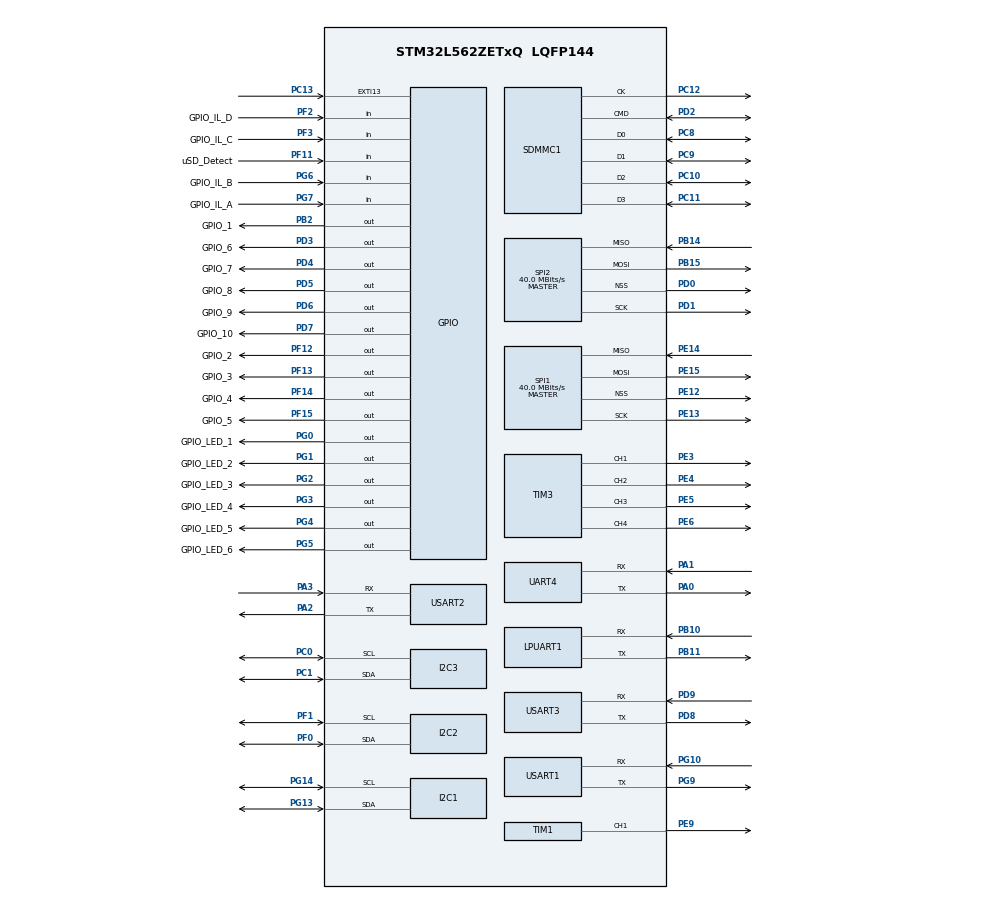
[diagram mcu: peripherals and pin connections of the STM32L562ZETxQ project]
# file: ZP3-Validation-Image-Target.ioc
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Dma.Request0=TIM1_CH1
Dma.TIM1_CH1.0.Channel_PRIV_NPRIV=DMA_CHANNEL_NPRIV_DISABLE
Dma.TIM1_CH1.0.Direction=DMA_MEMORY_TO_PERIPH
Dma.TIM1_CH1.0.EventEnable=DISABLE
Dma.TIM1_CH1.0.Instance=DMA1_Channel1
Dma.TIM1_CH1.0.MemDataAlignment=DMA_MDATAALIGN_HALFWORD
Dma.TIM1_CH1.0.MemInc=DMA_MINC_ENABLE
Dma.TIM1_CH1.0.Mode=DMA_NORMAL
Dma.TIM1_CH1.0.PeriphDataAlignment=DMA_PDATAALIGN_HALFWORD
Dma.TIM1_CH1.0.PeriphInc=DMA_PINC_DISABLE
Dma.TIM1_CH1.0.Polarity=HAL_DMAMUX_REQ_GEN_RISING
Dma.TIM1_CH1.0.Priority=DMA_PRIORITY_LOW
Dma.TIM1_CH1.0.RequestNumber=1
Dma.TIM1_CH1.0.SignalID=NONE
Dma.TIM1_CH1.0.SyncEnable=DISABLE
Dma.TIM1_CH1.0.SyncPolarity=HAL_DMAMUX_SYNC_NO_EVENT
Dma.TIM1_CH1.0.SyncRequestNumber=1
Dma.TIM1_CH1.0.SyncSignalID=NONE
I2C1.Timing=0x10909CEC
I2C2.Timing=0x10909CEC
I2C3.Timing=0x10909CEC
Mcu.Family=STM32L5
Mcu.Name=STM32L562ZETxQ
Mcu.Package=LQFP144
NVIC.DMA1_Channel1_IRQn=true\:0\:0\:false\:false\:true\:false\:true\:true
NVIC.PriorityGroup=NVIC_PRIORITYGROUP_3
NVIC.SDMMC1_IRQn=true\:0\:0\:false\:false\:true\:true\:true\:true
PA0.Mode=Asynchronous
PA0.Signal=UART4_TX
PA1.Mode=Asynchronous
PA1.Signal=UART4_RX
PA11.Signal=USART1_CTS
PA12.Signal=USART1_RTS
PA13\ (JTMS/SWDIO).GPIO_Label=SWDIO
PA13\ (JTMS/SWDIO).Signal=DEBUG_JTMS-SWDIO
PA14\ (JTCK/SWCLK).GPIO_Label=SWCLK
PA14\ (JTCK/SWCLK).Signal=DEBUG_JTCK-SWCLK
PA15\ (JTDI).Signal=UART4_RTS
PA2.Mode=Asynchronous
PA2.Signal=USART2_TX
PA3.Mode=Asynchronous
PA3.Signal=USART2_RX
PA4.GPIO_Label=PWR_SENSE
PA4.Signal=ADCx_IN9
PA6.Signal=ADCx_IN11
PA7.Signal=ADCx_IN12
PB0.Signal=ADCx_IN15
PB1.GPIO_Label=VBAT_A_SENSE
PB1.Signal=ADCx_IN16
PB10.Mode=Asynchronous
PB10.Signal=LPUART1_RX
PB11.Mode=Asynchronous
PB11.Signal=LPUART1_TX
PB14.Mode=Full_Duplex_Master
PB14.Signal=SPI2_MISO
PB15.Mode=Full_Duplex_Master
PB15.Signal=SPI2_MOSI
PB2.GPIO_Label=GPIO_1
PB2.Signal=GPIO_Output
PB3\ (JTDO/TRACESWO).GPIO_Label=SWO
PB3\ (JTDO/TRACESWO).Signal=DEBUG_JTDO-SWO
PB7.Signal=UART4_CTS
PB8.Signal=S_TIM16_CH1
PB9.Signal=S_TIM17_CH1
PC0.Mode=I2C
PC0.Signal=I2C3_SCL
PC1.Mode=I2C
PC1.Signal=I2C3_SDA
PC10.Mode=SD_4_bits_Wide_bus
PC10.Signal=SDMMC1_D2
PC11.Mode=SD_4_bits_Wide_bus
PC11.Signal=SDMMC1_D3
PC12.Mode=SD_4_bits_Wide_bus
PC12.Signal=SDMMC1_CK
PC13.Privilege=EXTI_LINE_PRIV
PC13.Signal=GPXTI13
PC2.GPIO_Label=VBAT_B_SENSE
PC2.Signal=ADCx_IN3
PC8.Mode=SD_4_bits_Wide_bus
PC8.Signal=SDMMC1_D0
PC9.Mode=SD_4_bits_Wide_bus
PC9.Signal=SDMMC1_D1
PD0.Mode=NSS_Signal_Hard_Output
PD0.Signal=SPI2_NSS
PD1.Mode=Full_Duplex_Master
PD1.Signal=SPI2_SCK
PD12.Signal=S_TIM4_CH1
PD13.Signal=S_TIM4_CH2
PD14.Signal=S_TIM4_CH3
PD2.Mode=SD_4_bits_Wide_bus
PD2.Signal=SDMMC1_CMD
PD3.GPIO_Label=GPIO_6
PD3.Signal=GPIO_Output
PD4.GPIO_Label=GPIO_7
PD4.Signal=GPIO_Output
PD5.GPIO_Label=GPIO_8
PD5.Signal=GPIO_Output
PD6.GPIO_Label=GPIO_9
PD6.Signal=GPIO_Output
PD7.GPIO_Label=GPIO_10
PD7.Signal=GPIO_Output
PD8.Mode=Asynchronous
PD8.Signal=USART3_TX
PD9.Mode=Asynchronous
PD9.Signal=USART3_RX
PE11.Signal=S_TIM1_CH2
PE12.Mode=NSS_Signal_Hard_Output
PE12.Signal=SPI1_NSS
PE13.Mode=Full_Duplex_Master
PE13.Signal=SPI1_SCK
PE14.Mode=Full_Duplex_Master
PE14.Signal=SPI1_MISO
PE15.Mode=Full_Duplex_Master
PE15.Signal=SPI1_MOSI
PE3.Signal=S_TIM3_CH1
PE4.Signal=S_TIM3_CH2
PE5.Signal=S_TIM3_CH3
PE6.Signal=S_TIM3_CH4
PE9.Signal=S_TIM1_CH1
PF0.Mode=I2C
PF0.Signal=I2C2_SDA
PF1.Mode=I2C
PF1.Signal=I2C2_SCL
PF11.GPIO_Label=uSD_Detect
PF11.Signal=GPIO_Input
PF12.GPIO_Label=GPIO_2
PF12.Signal=GPIO_Output
PF13.GPIO_Label=GPIO_3
PF13.Signal=GPIO_Output
PF14.GPIO_Label=GPIO_4
PF14.Signal=GPIO_Output
PF15.GPIO_Label=GPIO_5
PF15.Signal=GPIO_Output
PF2.GPIO_Label=GPIO_IL_D
PF2.Signal=GPIO_Input
PF3.GPIO_Label=GPIO_IL_C
PF3.Signal=GPIO_Input
PF6.Signal=S_TIM5_CH1
PF7.Signal=S_TIM5_CH2
PF8.Signal=S_TIM5_CH3
PF9.Signal=S_TIM5_CH4
PG0.GPIO_Label=GPIO_LED_1
PG0.Signal=GPIO_Output
PG1.GPIO_Label=GPIO_LED_2
PG1.Signal=GPIO_Output
PG10.Mode=Asynchronous
PG10.Signal=USART1_RX
PG13.Mode=I2C
PG13.Signal=I2C1_SDA
PG14.Mode=I2C
PG14.Signal=I2C1_SCL
PG2.GPIO_Label=GPIO_LED_3
PG2.Signal=GPIO_Output
PG3.GPIO_Label=GPIO_LED_4
PG3.Signal=GPIO_Output
PG4.GPIO_Label=GPIO_LED_5
PG4.Signal=GPIO_Output
PG5.GPIO_Label=GPIO_LED_6
PG5.Signal=GPIO_Output
PG6.GPIO_Label=GPIO_IL_B
PG6.Signal=GPIO_Input
PG7.GPIO_Label=GPIO_IL_A
PG7.Signal=GPIO_Input
PG9.Mode=Asynchronous
PG9.Signal=USART1_TX
PH0-OSC_IN\ (PH0).Mode=HSE-External-Oscillator
PH0-OSC_IN\ (PH0).Signal=RCC_OSC_IN
PH1-OSC_OUT\ (PH1).Mode=HSE-External-Oscillator
PH1-OSC_OUT\ (PH1).Signal=RCC_OSC_OUT
ProjectManager.HeapSize=0x400
ProjectManager.StackSize=0x800
ProjectManager.TargetToolchain=STM32CubeIDE
RCC.AHBFreq_Value=80000000
RCC.APB1Freq_Value=80000000
RCC.APB1TimFreq_Value=80000000
RCC.APB2Freq_Value=80000000
RCC.APB2TimFreq_Value=80000000
RCC.CortexFreq_Value=80000000
RCC.HCLKFreq_Value=80000000
RCC.HSE_VALUE=16000000
RCC.HSI48_VALUE=48000000
RCC.HSI_VALUE=16000000
RCC.LSE_VALUE=32768
RCC.MSI_VALUE=4000000
RCC.PLLN=40
RCC.SYSCLKFreq_VALUE=80000000
RCC.SYSCLKSource=RCC_SYSCLKSOURCE_PLLCLK
RCC.VCOOutputFreq_Value=160000000
SH.ADCx_IN11.0=ADC1_IN11
SH.ADCx_IN12.0=ADC1_IN12
SH.ADCx_IN15.0=ADC1_IN15
SH.ADCx_IN16.0=ADC2_IN16
SH.ADCx_IN3.0=ADC2_IN3
SH.ADCx_IN9.0=ADC2_IN9
SH.S_TIM16_CH1.0=TIM16_CH1
SH.S_TIM17_CH1.0=TIM17_CH1
SH.S_TIM1_CH1.0=TIM1_CH1,PWM Generation1 CH1
SH.S_TIM1_CH2.0=TIM1_CH2
SH.S_TIM3_CH1.0=TIM3_CH1,PWM Generation1 CH1
SH.S_TIM3_CH2.0=TIM3_CH2,PWM Generation2 CH2
SH.S_TIM3_CH3.0=TIM3_CH3,PWM Generation3 CH3
SH.S_TIM3_CH4.0=TIM3_CH4,PWM Generation4 CH4
SH.S_TIM4_CH1.0=TIM4_CH1
SH.S_TIM4_CH2.0=TIM4_CH2
SH.S_TIM4_CH3.0=TIM4_CH3
SH.S_TIM5_CH1.0=TIM5_CH1
SH.S_TIM5_CH2.0=TIM5_CH2
SH.S_TIM5_CH3.0=TIM5_CH3
SH.S_TIM5_CH4.0=TIM5_CH4
SPI1.BaudRatePrescaler=SPI_BAUDRATEPRESCALER_2
SPI1.CalculateBaudRate=40.0 MBits/s
SPI1.Direction=SPI_DIRECTION_2LINES
SPI1.Mode=SPI_MODE_MASTER
SPI1.VirtualNSS=VM_NSSHARD
SPI1.VirtualType=VM_MASTER
SPI2.BaudRatePrescaler=SPI_BAUDRATEPRESCALER_2
SPI2.CalculateBaudRate=40.0 MBits/s
SPI2.Direction=SPI_DIRECTION_2LINES
SPI2.Mode=SPI_MODE_MASTER
SPI2.VirtualNSS=VM_NSSHARD
SPI2.VirtualType=VM_MASTER
TIM1.Channel-PWM\ Generation1\ CH1=TIM_CHANNEL_1
TIM1.Period=100-1
TIM3.AutoReloadPreload=TIM_AUTORELOAD_PRELOAD_ENABLE
TIM3.Channel-PWM\ Generation1\ CH1=TIM_CHANNEL_1
TIM3.Channel-PWM\ Generation2\ CH2=TIM_CHANNEL_2
TIM3.Channel-PWM\ Generation3\ CH3=TIM_CHANNEL_3
TIM3.Channel-PWM\ Generation4\ CH4=TIM_CHANNEL_4
USART1.VirtualMode-Asynchronous=VM_ASYNC
USART2.VirtualMode-Asynchronous=VM_ASYNC
USART3.VirtualMode-Asynchronous=VM_ASYNC
VP_FATFS_VS_SDIO.Mode=SDIO
VP_PWR_VS_DBSignals.Mode=DisableDeadBatterySignals
VP_PWR_VS_SECSignals.Mode=Security/Privilege
VP_TIM3_VS_ClockSourceINT.Mode=Internal
board=custom

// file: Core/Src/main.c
/* USER CODE BEGIN Header */

/**

  ******************************************************************************

  * @file           : main.c

  * @brief          : Main program body

  ******************************************************************************

  * @attention

  *

  * Copyright (c) 2024 STMicroelectronics.

  * All rights reserved.

  *

  * This software is licensed under terms that can be found in the LICENSE file

  * in the root directory of this software component.

  * If no LICENSE file comes with this software, it is provided AS-IS.

  *

  ******************************************************************************

  */

/* USER CODE END Header */

#include "main.h"

#include "dma.h"

#include "app_fatfs.h"

#include "i2c.h"

#include "usart.h"

#include "sdmmc.h"

#include "spi.h"

#include "tim.h"

#include "gpio.h"

/* USER CODE BEGIN Includes */

#include "string.h"

#include "stdio.h"

/* USER CODE END Includes */

/* USER CODE BEGIN PD */

#define LOW GPIO_PIN_RESET

#define HIGH GPIO_PIN_SET

/* USER CODE END PD */

/* USER CODE BEGIN PV */
TIM_HandleTypeDef htim3;
uint16_t pwmData[24];

int datasentflag = 0;

/* USER CODE END PV */

/* USER CODE BEGIN PFP */

void LED_Test(void);

void GPIO_Test(void);

void UART_Test(void);

void I2C_Test(void);

void SPI_Test(void);
void SPI_Test_2(void);

void PWM_Gen(void);

void PWM_DMA_Gen(TIM_HandleTypeDef *);

void Transmit_Sequence(TIM_HandleTypeDef *, uint32_t);

void ADC_Test(void);

void MicroSD_Test(void);

void Interlock_Check(void);

void SystemClock_Config(void);
void Error_Handler(void);
void MX_GPIO_Init(void);
void MX_TIM3_Init(void);
void Start_PWM(void);

/* USER CODE END PFP */

int main(void){

  /* MCU Configuration--------------------------------------------------------*/

  /* Reset of all peripherals, Initializes the Flash interface and the Systick. */

  HAL_Init();

  /* Configure the system clock */

  SystemClock_Config();

  /* Initialize all configured peripherals */

  MX_GPIO_Init();

  MX_DMA_Init();

  MX_USART2_UART_Init();

  MX_USART3_UART_Init();

  MX_SDMMC1_SD_Init();

  if (MX_FATFS_Init() != APP_OK) {

    Error_Handler();

  }

  MX_I2C1_Init();

  MX_I2C2_Init();

  MX_I2C3_Init();

  MX_SPI1_Init();

  MX_SPI2_Init();

  MX_TIM1_Init();

  MX_TIM3_Init();

  MX_USART1_UART_Init();

  MX_LPUART1_UART_Init();

  MX_UART4_Init();

  HAL_TIM_PWM_Start(&htim3, TIM_CHANNEL_1);

  HAL_TIM_PWM_Start(&htim3, TIM_CHANNEL_2);

  HAL_TIM_PWM_Start(&htim3, TIM_CHANNEL_3);

  HAL_TIM_PWM_Start(&htim3, TIM_CHANNEL_4);

  /* Infinite loop */

  while (1)
  {

  }

}

void SystemClock_Config(void)
{
  RCC_OscInitTypeDef RCC_OscInitStruct = {0};
  RCC_ClkInitTypeDef RCC_ClkInitStruct = {0};

  // Configure the main internal regulator output voltage
  if (HAL_PWREx_ControlVoltageScaling(PWR_REGULATOR_VOLTAGE_SCALE1) != HAL_OK)
  {
    Error_Handler();
  }

  // Initializes the RCC Oscillators according to the specified parameters
  RCC_OscInitStruct.OscillatorType = RCC_OSCILLATORTYPE_HSE;
  RCC_OscInitStruct.HSEState = RCC_HSE_ON;
  RCC_OscInitStruct.PLL.PLLState = RCC_PLL_ON;
  RCC_OscInitStruct.PLL.PLLSource = RCC_PLLSOURCE_HSE;
  RCC_OscInitStruct.PLL.PLLM = 1; // Division factor for PLL input clock (HSE / PLLM)
  RCC_OscInitStruct.PLL.PLLN = 72; // Multiplication factor for PLL VCO (VCO = HSE * PLLN)
  RCC_OscInitStruct.PLL.PLLP = RCC_PLLP_DIV2; // Division factor for main system clock (VCO / PLLP)
  RCC_OscInitStruct.PLL.PLLQ = RCC_PLLQ_DIV2; // Division factor for USB clock (48 MHz)
  RCC_OscInitStruct.PLL.PLLR = RCC_PLLR_DIV2; // Division factor for other clock sources

  if (HAL_RCC_OscConfig(&RCC_OscInitStruct) != HAL_OK)
  {
    Error_Handler();
  }

  // Initializes the CPU, AHB and APB buses clocks
  RCC_ClkInitStruct.ClockType = RCC_CLOCKTYPE_HCLK | RCC_CLOCKTYPE_SYSCLK |
                                RCC_CLOCKTYPE_PCLK1 | RCC_CLOCKTYPE_PCLK2;
  RCC_ClkInitStruct.SYSCLKSource = RCC_SYSCLKSOURCE_PLLCLK;
  RCC_ClkInitStruct.AHBCLKDivider = RCC_SYSCLK_DIV1;
  RCC_ClkInitStruct.APB1CLKDivider = RCC_HCLK_DIV2;
  RCC_ClkInitStruct.APB2CLKDivider = RCC_HCLK_DIV1;

  if (HAL_RCC_ClockConfig(&RCC_ClkInitStruct, FLASH_LATENCY_2) != HAL_OK)
  {
    Error_Handler();
  }

  // Configure the Systick interrupt time
  HAL_SYSTICK_Config(HAL_RCC_GetHCLKFreq()/1000);

  // Configure the Systick
  HAL_SYSTICK_CLKSourceConfig(SYSTICK_CLKSOURCE_HCLK);

  // SysTick_IRQn interrupt configuration
  HAL_NVIC_SetPriority(SysTick_IRQn, 0, 0);

  /** Enable MSI Auto calibration

  */

  HAL_RCCEx_EnableMSIPLLMode();

}

void MX_TIM3_Init(void)
{
  TIM_OC_InitTypeDef sConfigOC = {0};

  // Enable timer clock
  __HAL_RCC_TIM3_CLK_ENABLE();

  // Basic timer configuration
  htim3.Instance = TIM3;
  htim3.Init.Prescaler = 0;
  htim3.Init.CounterMode = TIM_COUNTERMODE_UP;
  htim3.Init.Period = 500; // Adjust based on desired frequency
  htim3.Init.ClockDivision = TIM_CLOCKDIVISION_DIV1;
  htim3.Init.AutoReloadPreload = TIM_AUTORELOAD_PRELOAD_DISABLE;

  if (HAL_TIM_PWM_Init(&htim3) != HAL_OK)
  {
    // Initialization Error
    Error_Handler();
  }

  // PWM mode configuration
  sConfigOC.OCMode = TIM_OCMODE_PWM1;
  sConfigOC.Pulse = 100; // Initial duty cycle value (between 0 and Period value)
  sConfigOC.OCPolarity = TIM_OCPOLARITY_HIGH;
  sConfigOC.OCFastMode = TIM_OCFAST_DISABLE;

  // Configure PWM Channel 1
  if (HAL_TIM_PWM_ConfigChannel(&htim3, &sConfigOC, TIM_CHANNEL_1) != HAL_OK)
  {
    // Configuration Error
    Error_Handler();
  }

  // Configure PWM Channel 2
  if (HAL_TIM_PWM_ConfigChannel(&htim3, &sConfigOC, TIM_CHANNEL_2) != HAL_OK)
  {
    // Configuration Error
    Error_Handler();
  }

  // Configure PWM Channel 3
  if (HAL_TIM_PWM_ConfigChannel(&htim3, &sConfigOC, TIM_CHANNEL_3) != HAL_OK)
  {
    // Configuration Error
    Error_Handler();
  }

  // Configure PWM Channel 4
  if (HAL_TIM_PWM_ConfigChannel(&htim3, &sConfigOC, TIM_CHANNEL_4) != HAL_OK)
  {
    // Configuration Error
    Error_Handler();
  }
}

/* USER CODE BEGIN 4 */

void GPIOTest(void)

{

      while(1)

      {

            // Drive all GPIO Pins LOW

            HAL_GPIO_WritePin(GPIO_1_GPIO_Port, GPIO_1_Pin, GPIO_PIN_RESET);

            HAL_GPIO_WritePin(GPIO_2_GPIO_Port, GPIO_2_Pin, GPIO_PIN_RESET);

            HAL_GPIO_WritePin(GPIO_3_GPIO_Port, GPIO_3_Pin, GPIO_PIN_RESET);

            HAL_GPIO_WritePin(GPIO_4_GPIO_Port, GPIO_4_Pin, GPIO_PIN_RESET);

            HAL_GPIO_WritePin(GPIO_5_GPIO_Port, GPIO_5_Pin, GPIO_PIN_RESET);

            HAL_GPIO_WritePin(GPIO_6_GPIO_Port, GPIO_6_Pin, GPIO_PIN_RESET);

            HAL_GPIO_WritePin(GPIO_7_GPIO_Port, GPIO_7_Pin, GPIO_PIN_RESET);

            HAL_GPIO_WritePin(GPIO_8_GPIO_Port, GPIO_8_Pin, GPIO_PIN_RESET);

            HAL_GPIO_WritePin(GPIO_9_GPIO_Port, GPIO_9_Pin, GPIO_PIN_RESET);

            HAL_GPIO_WritePin(GPIO_10_GPIO_Port, GPIO_10_Pin, GPIO_PIN_RESET);

            HAL_Delay(100);

            // Drive all GPIO Pins HIGH

            HAL_GPIO_WritePin(GPIO_1_GPIO_Port, GPIO_1_Pin, GPIO_PIN_SET);

            HAL_GPIO_WritePin(GPIO_2_GPIO_Port, GPIO_2_Pin, GPIO_PIN_SET);

            HAL_GPIO_WritePin(GPIO_3_GPIO_Port, GPIO_3_Pin, GPIO_PIN_SET);

            HAL_GPIO_WritePin(GPIO_4_GPIO_Port, GPIO_4_Pin, GPIO_PIN_SET);

            HAL_GPIO_WritePin(GPIO_5_GPIO_Port, GPIO_5_Pin, GPIO_PIN_SET);

            HAL_GPIO_WritePin(GPIO_6_GPIO_Port, GPIO_6_Pin, GPIO_PIN_SET);

            HAL_GPIO_WritePin(GPIO_7_GPIO_Port, GPIO_7_Pin, GPIO_PIN_SET);

            HAL_GPIO_WritePin(GPIO_8_GPIO_Port, GPIO_8_Pin, GPIO_PIN_SET);

            HAL_GPIO_WritePin(GPIO_9_GPIO_Port, GPIO_9_Pin, GPIO_PIN_SET);

            HAL_GPIO_WritePin(GPIO_10_GPIO_Port, GPIO_10_Pin, GPIO_PIN_SET);

            HAL_Delay(100);

      }

}

void UART_Test(void)

{

      uint8_t UART_Buff[16] = {0};

      // LPUART1

      HAL_UART_Receive(&hlpuart1, UART_Buff, 16, HAL_MAX_DELAY);

      HAL_UART_Transmit(&hlpuart1, UART_Buff, 16, 100);

      memset(UART_Buff, 0, sizeof(UART_Buff));

      // USART1

      HAL_UART_Receive(&huart1, UART_Buff, 16, HAL_MAX_DELAY);

      HAL_UART_Transmit(&huart1, UART_Buff, 16, 100);

      memset(UART_Buff, 0, sizeof(UART_Buff));

      // USART2

      HAL_UART_Receive(&huart2, UART_Buff, 16, HAL_MAX_DELAY);

      HAL_UART_Transmit(&huart2, UART_Buff, 16, 100);

      memset(UART_Buff, 0, sizeof(UART_Buff));

      // USART3

      HAL_UART_Receive(&huart3, UART_Buff, 16, HAL_MAX_DELAY);

      HAL_UART_Transmit(&huart3, UART_Buff, 16, 100);

      memset(UART_Buff, 0, sizeof(UART_Buff));

      // UART4

      HAL_UART_Receive(&huart4, UART_Buff, 16, HAL_MAX_DELAY);

      HAL_UART_Transmit(&huart4, UART_Buff, 16, 100);

      memset(UART_Buff, 0, sizeof(UART_Buff));

}

void I2C_Test(void)

{

      uint8_t I2C_Buff[16] = {0};

      // I2C1

      HAL_I2C_Slave_Receive(&hi2c1, I2C_Buff, 16, HAL_MAX_DELAY);

      HAL_I2C_Slave_Transmit(&hi2c1, I2C_Buff, 16, 100);

      memset(I2C_Buff, 0, 16*sizeof(I2C_Buff[0]));

      // I2C2

      HAL_I2C_Slave_Receive(&hi2c2, I2C_Buff, 16, HAL_MAX_DELAY);

      HAL_I2C_Slave_Transmit(&hi2c2, I2C_Buff, 16, 100);

      memset(I2C_Buff, 0, 16*sizeof(I2C_Buff[0]));

      // I2C3

      HAL_I2C_Slave_Receive(&hi2c3, I2C_Buff, 16, HAL_MAX_DELAY);

      HAL_I2C_Slave_Transmit(&hi2c3, I2C_Buff, 16, 100);

      memset(I2C_Buff, 0, 16*sizeof(I2C_Buff[0]));

}

void SPI_Test(void){

      uint8_t SPI_Transmit_Data [0x10]={0};

      HAL_GPIO_WritePin(GPIOE, GPIO_PIN_12, GPIO_PIN_RESET);

      HAL_SPI_Receive(&hspi1, SPI_Transmit_Data, sizeof(SPI_Transmit_Data),HAL_MAX_DELAY);

      HAL_SPI_Transmit(&hspi1, SPI_Transmit_Data, sizeof(SPI_Transmit_Data),100);

      HAL_GPIO_WritePin(GPIOE, GPIO_PIN_12, GPIO_PIN_SET);

}

void SPI_Test_2(void){

	  uint8_t SPI_Transmit_Data [0x10]={0};

	  HAL_GPIO_WritePin(GPIOD, GPIO_PIN_0, GPIO_PIN_RESET);

	  HAL_SPI_Receive(&hspi2, SPI_Transmit_Data, sizeof(SPI_Transmit_Data),HAL_MAX_DELAY);

	  HAL_SPI_Transmit(&hspi2, SPI_Transmit_Data, sizeof(SPI_Transmit_Data),100);

	  HAL_GPIO_WritePin(GPIOD, GPIO_PIN_0, GPIO_PIN_SET);
}

void MicroSD_Test(void)

{

      FRESULT res; /* FatFs function common result code */

      uint32_t byteswritten; // File write

      // uint32_t bytesread; // Read count

      uint8_t wtext[] = "STM32 FATFS works great!"; /* File write buffer */

      uint8_t rtext[_MAX_SS];/* File read buffer */

      if(f_mount(&SDFatFS, (TCHAR const*)SDPath, 0) != FR_OK)

      {

            Error_Handler();

      }

      else

      {

            if(f_mkfs((TCHAR const*)SDPath, FM_ANY, 0, rtext, sizeof(rtext)) != FR_OK)

            {

                  Error_Handler();

            }

            else

            {

                  //Open file for writing (Create)

                  if(f_open(&SDFile, "STM32.TXT", FA_CREATE_ALWAYS | FA_WRITE) != FR_OK)

                  {

                        Error_Handler();

                  }

                  else

                  {

                        //Write to the text file

                        res = f_write(&SDFile, wtext, strlen((char *)wtext), (void *)&byteswritten);

                        if((byteswritten == 0) || (res != FR_OK))

                        {

                              Error_Handler();

                        }

                        else

                        {

                              f_close(&SDFile);

                        }

                  }

            }

      }

      f_mount(&SDFatFS, (TCHAR const*)NULL, 0);

}

void PWM_DMA_GEN(TIM_HandleTypeDef *htim)

{

      uint32_t sequence = 0xAAAAAAAA; // binary sequence

      Transmit_Sequence(htim, sequence);

}

/*

* PWM_DMA_GEN Helper function that takes in a binary sequence and sets the pwmdata

*/

void Transmit_Sequence (TIM_HandleTypeDef *htim, uint32_t sequence)

{

      // Transfer bit sequence to pwmData array

      for (int i=23; i>=0; i--)

      {

            if (sequence&(1<<i))

            {

                  pwmData[i] = 50;

            }

            else pwmData[i] = 25;

      }

      HAL_TIM_PWM_Start_DMA(htim, TIM_CHANNEL_1, (uint32_t *)pwmData, 24);

      while(!datasentflag){};

      datasentflag = 0;

}

void HAL_TIM_PWM_PulseFinishedCallback(TIM_HandleTypeDef *htim)

{

      HAL_TIM_PWM_Stop_DMA(htim, TIM_CHANNEL_1);

      datasentflag = 1;

}

/*

* Check GPIO Interlock Channels, should read HIGH.

*/

void Interlock_Check(void)

{

      char uartBuf[100];

      if(HAL_GPIO_ReadPin(GPIO_IL_A_GPIO_Port, GPIO_IL_A_Pin))

      {

            sprintf(uartBuf, "[OK]  GPIO_IL_A\n");

            HAL_UART_Transmit(&huart1, (uint8_t *)uartBuf, strlen(uartBuf), 100);

      }

      if(HAL_GPIO_ReadPin(GPIO_IL_B_GPIO_Port, GPIO_IL_B_Pin))

      {

            sprintf(uartBuf, "[OK]  GPIO_IL_B\n");

            HAL_UART_Transmit(&huart1, (uint8_t *)uartBuf, strlen(uartBuf), 100);

      }

      if(HAL_GPIO_ReadPin(GPIO_IL_C_GPIO_Port, GPIO_IL_C_Pin))

      {

            sprintf(uartBuf, "[OK]  GPIO_IL_C\n");

            HAL_UART_Transmit(&huart1, (uint8_t *)uartBuf, strlen(uartBuf), 100);

      }

      if(HAL_GPIO_ReadPin(GPIO_IL_D_GPIO_Port, GPIO_IL_D_Pin))

      {

            sprintf(uartBuf, "[OK]  GPIO_IL_D\n" );

            HAL_UART_Transmit(&huart1, (uint8_t *)uartBuf, strlen(uartBuf), 100);

      }

}

void Start_PWM(void)
{
    if (HAL_TIM_PWM_Start(&htim3, TIM_CHANNEL_1) != HAL_OK)
    {
        // PWM Generation Error
        Error_Handler();
    }
}

void Set_PWM_DutyCycle(uint32_t dutyCycle)
{
  TIM_OC_InitTypeDef sConfigOC = {0};
  sConfigOC.OCMode = TIM_OCMODE_PWM1;
  sConfigOC.Pulse = dutyCycle; // Duty cycle value (between 0 and Period value)
  sConfigOC.OCPolarity = TIM_OCPOLARITY_HIGH;
  sConfigOC.OCFastMode = TIM_OCFAST_DISABLE;

  if (HAL_TIM_PWM_ConfigChannel(&htim3, &sConfigOC, TIM_CHANNEL_1) != HAL_OK)
  {
    // Configuration Error
    Error_Handler();
  }

  if (HAL_TIM_PWM_ConfigChannel(&htim3, &sConfigOC, TIM_CHANNEL_2) != HAL_OK)
  {
    // Configuration Error
    Error_Handler();
  }

  if (HAL_TIM_PWM_ConfigChannel(&htim3, &sConfigOC, TIM_CHANNEL_3) != HAL_OK)
  {
    // Configuration Error
    Error_Handler();
  }

  if (HAL_TIM_PWM_ConfigChannel(&htim3, &sConfigOC, TIM_CHANNEL_4) != HAL_OK)
  {
    // Configuration Error
    Error_Handler();
  }

  if (HAL_TIM_PWM_Start(&htim3, TIM_CHANNEL_1) != HAL_OK)
  {
    // PWM Generation Error
    Error_Handler();
  }

  if (HAL_TIM_PWM_Start(&htim3, TIM_CHANNEL_2) != HAL_OK)
  {
    // PWM Generation Error
    Error_Handler();
  }

  if (HAL_TIM_PWM_Start(&htim3, TIM_CHANNEL_3) != HAL_OK)
  {
    // PWM Generation Error
    Error_Handler();
  }

  if (HAL_TIM_PWM_Start(&htim3, TIM_CHANNEL_4) != HAL_OK)
  {
    // PWM Generation Error
    Error_Handler();
  }
}

void PWM_GEN(){

	// HAL Initialization
	    HAL_Init();

	    // System Clock Configuration
	    SystemClock_Config();

	    // Initialize all configured peripherals
	    TIM3_PWM_Init();

	    // Start PWM
	    Start_PWM();

	    // Main loop
	    while (1)
	    {
	        // Adjust duty cycle as needed
	        Set_PWM_DutyCycle(750); // Example duty cycle value
	        HAL_Delay(1000);
	        Set_PWM_DutyCycle(250); // Example duty cycle value
	        HAL_Delay(1000);
	    }

}

/* USER CODE END 4 */

void Error_Handler(void)

{

  __disable_irq();
  while (1)
  {
  }

}
